VERSION 5.7 ;
  NOWIREEXTENSIONATPIN ON ;
  DIVIDERCHAR "/" ;
  BUSBITCHARS "[]" ;
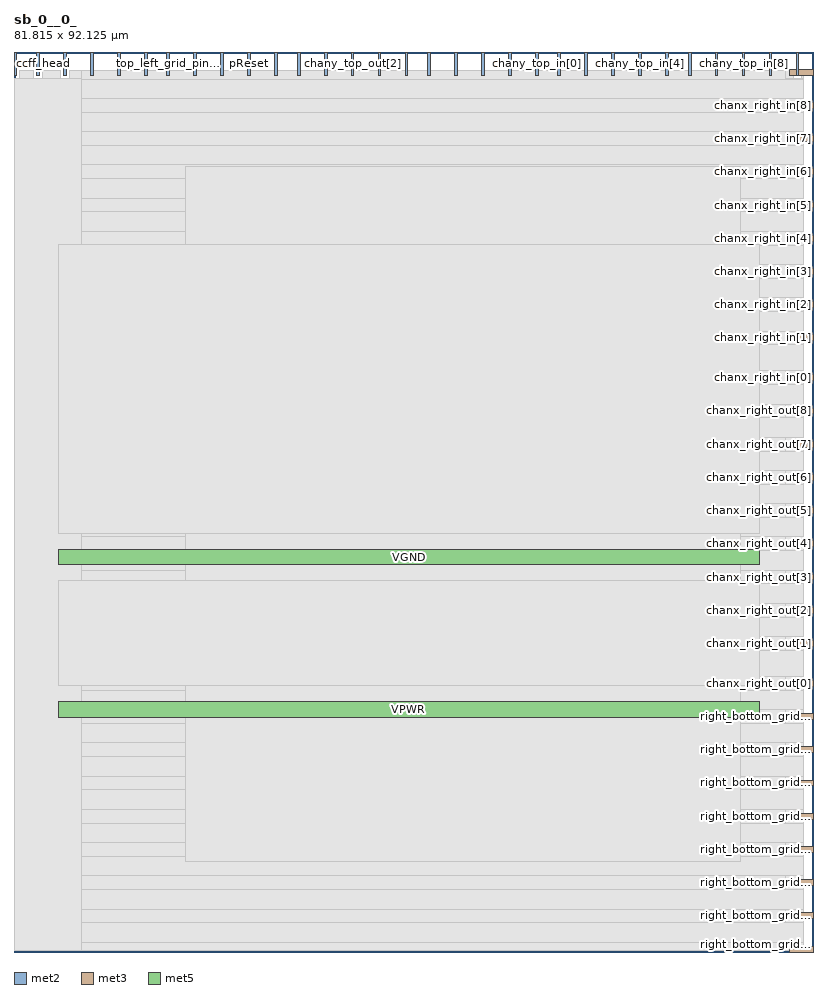
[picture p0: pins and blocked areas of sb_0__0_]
MACRO sb_0__0_
  CLASS BLOCK ;
  FOREIGN sb_0__0_ ;
  ORIGIN 0.000 0.000 ;
  SIZE 81.815 BY 92.125 ;
  PIN ccff_head
    DIRECTION INPUT ;
    PORT
      LAYER met2 ;
        RECT 0.020 89.725 0.300 92.125 ;
    END
  END ccff_head
  PIN ccff_tail
    DIRECTION OUTPUT TRISTATE ;
    PORT
      LAYER met2 ;
        RECT 77.300 89.725 77.580 92.125 ;
    END
  END ccff_tail
  PIN chanx_right_in[0]
    DIRECTION INPUT ;
    PORT
      LAYER met3 ;
        RECT 79.415 58.480 81.815 59.080 ;
    END
  END chanx_right_in[0]
  PIN chanx_right_in[1]
    DIRECTION INPUT ;
    PORT
      LAYER met3 ;
        RECT 79.415 62.560 81.815 63.160 ;
    END
  END chanx_right_in[1]
  PIN chanx_right_in[2]
    DIRECTION INPUT ;
    PORT
      LAYER met3 ;
        RECT 79.415 65.960 81.815 66.560 ;
    END
  END chanx_right_in[2]
  PIN chanx_right_in[3]
    DIRECTION INPUT ;
    PORT
      LAYER met3 ;
        RECT 79.415 69.360 81.815 69.960 ;
    END
  END chanx_right_in[3]
  PIN chanx_right_in[4]
    DIRECTION INPUT ;
    PORT
      LAYER met3 ;
        RECT 79.415 72.760 81.815 73.360 ;
    END
  END chanx_right_in[4]
  PIN chanx_right_in[5]
    DIRECTION INPUT ;
    PORT
      LAYER met3 ;
        RECT 79.415 76.160 81.815 76.760 ;
    END
  END chanx_right_in[5]
  PIN chanx_right_in[6]
    DIRECTION INPUT ;
    PORT
      LAYER met3 ;
        RECT 79.415 79.560 81.815 80.160 ;
    END
  END chanx_right_in[6]
  PIN chanx_right_in[7]
    DIRECTION INPUT ;
    PORT
      LAYER met3 ;
        RECT 79.415 82.960 81.815 83.560 ;
    END
  END chanx_right_in[7]
  PIN chanx_right_in[8]
    DIRECTION INPUT ;
    PORT
      LAYER met3 ;
        RECT 79.415 86.360 81.815 86.960 ;
    END
  END chanx_right_in[8]
  PIN chanx_right_out[0]
    DIRECTION OUTPUT TRISTATE ;
    PORT
      LAYER met3 ;
        RECT 79.415 27.200 81.815 27.800 ;
    END
  END chanx_right_out[0]
  PIN chanx_right_out[1]
    DIRECTION OUTPUT TRISTATE ;
    PORT
      LAYER met3 ;
        RECT 79.415 31.280 81.815 31.880 ;
    END
  END chanx_right_out[1]
  PIN chanx_right_out[2]
    DIRECTION OUTPUT TRISTATE ;
    PORT
      LAYER met3 ;
        RECT 79.415 34.680 81.815 35.280 ;
    END
  END chanx_right_out[2]
  PIN chanx_right_out[3]
    DIRECTION OUTPUT TRISTATE ;
    PORT
      LAYER met3 ;
        RECT 79.415 38.080 81.815 38.680 ;
    END
  END chanx_right_out[3]
  PIN chanx_right_out[4]
    DIRECTION OUTPUT TRISTATE ;
    PORT
      LAYER met3 ;
        RECT 79.415 41.480 81.815 42.080 ;
    END
  END chanx_right_out[4]
  PIN chanx_right_out[5]
    DIRECTION OUTPUT TRISTATE ;
    PORT
      LAYER met3 ;
        RECT 79.415 44.880 81.815 45.480 ;
    END
  END chanx_right_out[5]
  PIN chanx_right_out[6]
    DIRECTION OUTPUT TRISTATE ;
    PORT
      LAYER met3 ;
        RECT 79.415 48.280 81.815 48.880 ;
    END
  END chanx_right_out[6]
  PIN chanx_right_out[7]
    DIRECTION OUTPUT TRISTATE ;
    PORT
      LAYER met3 ;
        RECT 79.415 51.680 81.815 52.280 ;
    END
  END chanx_right_out[7]
  PIN chanx_right_out[8]
    DIRECTION OUTPUT TRISTATE ;
    PORT
      LAYER met3 ;
        RECT 79.415 55.080 81.815 55.680 ;
    END
  END chanx_right_out[8]
  PIN chany_top_in[0]
    DIRECTION INPUT ;
    PORT
      LAYER met2 ;
        RECT 53.380 89.725 53.660 92.125 ;
    END
  END chany_top_in[0]
  PIN chany_top_in[1]
    DIRECTION INPUT ;
    PORT
      LAYER met2 ;
        RECT 55.680 89.725 55.960 92.125 ;
    END
  END chany_top_in[1]
  PIN chany_top_in[2]
    DIRECTION INPUT ;
    PORT
      LAYER met2 ;
        RECT 58.440 89.725 58.720 92.125 ;
    END
  END chany_top_in[2]
  PIN chany_top_in[3]
    DIRECTION INPUT ;
    PORT
      LAYER met2 ;
        RECT 61.200 89.725 61.480 92.125 ;
    END
  END chany_top_in[3]
  PIN chany_top_in[4]
    DIRECTION INPUT ;
    PORT
      LAYER met2 ;
        RECT 63.960 89.725 64.240 92.125 ;
    END
  END chany_top_in[4]
  PIN chany_top_in[5]
    DIRECTION INPUT ;
    PORT
      LAYER met2 ;
        RECT 66.720 89.725 67.000 92.125 ;
    END
  END chany_top_in[5]
  PIN chany_top_in[6]
    DIRECTION INPUT ;
    PORT
      LAYER met2 ;
        RECT 69.020 89.725 69.300 92.125 ;
    END
  END chany_top_in[6]
  PIN chany_top_in[7]
    DIRECTION INPUT ;
    PORT
      LAYER met2 ;
        RECT 71.780 89.725 72.060 92.125 ;
    END
  END chany_top_in[7]
  PIN chany_top_in[8]
    DIRECTION INPUT ;
    PORT
      LAYER met2 ;
        RECT 74.540 89.725 74.820 92.125 ;
    END
  END chany_top_in[8]
  PIN chany_top_out[0]
    DIRECTION OUTPUT TRISTATE ;
    PORT
      LAYER met2 ;
        RECT 29.000 89.725 29.280 92.125 ;
    END
  END chany_top_out[0]
  PIN chany_top_out[1]
    DIRECTION OUTPUT TRISTATE ;
    PORT
      LAYER met2 ;
        RECT 31.760 89.725 32.040 92.125 ;
    END
  END chany_top_out[1]
  PIN chany_top_out[2]
    DIRECTION OUTPUT TRISTATE ;
    PORT
      LAYER met2 ;
        RECT 34.520 89.725 34.800 92.125 ;
    END
  END chany_top_out[2]
  PIN chany_top_out[3]
    DIRECTION OUTPUT TRISTATE ;
    PORT
      LAYER met2 ;
        RECT 37.280 89.725 37.560 92.125 ;
    END
  END chany_top_out[3]
  PIN chany_top_out[4]
    DIRECTION OUTPUT TRISTATE ;
    PORT
      LAYER met2 ;
        RECT 40.040 89.725 40.320 92.125 ;
    END
  END chany_top_out[4]
  PIN chany_top_out[5]
    DIRECTION OUTPUT TRISTATE ;
    PORT
      LAYER met2 ;
        RECT 42.340 89.725 42.620 92.125 ;
    END
  END chany_top_out[5]
  PIN chany_top_out[6]
    DIRECTION OUTPUT TRISTATE ;
    PORT
      LAYER met2 ;
        RECT 45.100 89.725 45.380 92.125 ;
    END
  END chany_top_out[6]
  PIN chany_top_out[7]
    DIRECTION OUTPUT TRISTATE ;
    PORT
      LAYER met2 ;
        RECT 47.860 89.725 48.140 92.125 ;
    END
  END chany_top_out[7]
  PIN chany_top_out[8]
    DIRECTION OUTPUT TRISTATE ;
    PORT
      LAYER met2 ;
        RECT 50.620 89.725 50.900 92.125 ;
    END
  END chany_top_out[8]
  PIN pReset
    DIRECTION INPUT ;
    PORT
      LAYER met2 ;
        RECT 23.940 89.725 24.220 92.125 ;
    END
  END pReset
  PIN prog_clk
    DIRECTION INPUT ;
    PORT
      LAYER met2 ;
        RECT 26.700 89.725 26.980 92.125 ;
    END
  END prog_clk
  PIN right_bottom_grid_pin_11_
    DIRECTION INPUT ;
    PORT
      LAYER met3 ;
        RECT 79.415 17.000 81.815 17.600 ;
    END
  END right_bottom_grid_pin_11_
  PIN right_bottom_grid_pin_13_
    DIRECTION INPUT ;
    PORT
      LAYER met3 ;
        RECT 79.415 20.400 81.815 21.000 ;
    END
  END right_bottom_grid_pin_13_
  PIN right_bottom_grid_pin_15_
    DIRECTION INPUT ;
    PORT
      LAYER met3 ;
        RECT 79.415 23.800 81.815 24.400 ;
    END
  END right_bottom_grid_pin_15_
  PIN right_bottom_grid_pin_1_
    DIRECTION INPUT ;
    PORT
      LAYER met3 ;
        RECT 79.415 0.000 81.815 0.600 ;
    END
  END right_bottom_grid_pin_1_
  PIN right_bottom_grid_pin_3_
    DIRECTION INPUT ;
    PORT
      LAYER met3 ;
        RECT 79.415 3.400 81.815 4.000 ;
    END
  END right_bottom_grid_pin_3_
  PIN right_bottom_grid_pin_5_
    DIRECTION INPUT ;
    PORT
      LAYER met3 ;
        RECT 79.415 6.800 81.815 7.400 ;
    END
  END right_bottom_grid_pin_5_
  PIN right_bottom_grid_pin_7_
    DIRECTION INPUT ;
    PORT
      LAYER met3 ;
        RECT 79.415 10.200 81.815 10.800 ;
    END
  END right_bottom_grid_pin_7_
  PIN right_bottom_grid_pin_9_
    DIRECTION INPUT ;
    PORT
      LAYER met3 ;
        RECT 79.415 13.600 81.815 14.200 ;
    END
  END right_bottom_grid_pin_9_
  PIN right_top_grid_pin_10_
    DIRECTION INPUT ;
    PORT
      LAYER met3 ;
        RECT 79.415 89.760 81.815 90.360 ;
    END
  END right_top_grid_pin_10_
  PIN top_left_grid_pin_11_
    DIRECTION INPUT ;
    PORT
      LAYER met2 ;
        RECT 15.660 89.725 15.940 92.125 ;
    END
  END top_left_grid_pin_11_
  PIN top_left_grid_pin_13_
    DIRECTION INPUT ;
    PORT
      LAYER met2 ;
        RECT 18.420 89.725 18.700 92.125 ;
    END
  END top_left_grid_pin_13_
  PIN top_left_grid_pin_15_
    DIRECTION INPUT ;
    PORT
      LAYER met2 ;
        RECT 21.180 89.725 21.460 92.125 ;
    END
  END top_left_grid_pin_15_
  PIN top_left_grid_pin_1_
    DIRECTION INPUT ;
    PORT
      LAYER met2 ;
        RECT 2.320 89.725 2.600 92.125 ;
    END
  END top_left_grid_pin_1_
  PIN top_left_grid_pin_3_
    DIRECTION INPUT ;
    PORT
      LAYER met2 ;
        RECT 5.080 89.725 5.360 92.125 ;
    END
  END top_left_grid_pin_3_
  PIN top_left_grid_pin_5_
    DIRECTION INPUT ;
    PORT
      LAYER met2 ;
        RECT 7.840 89.725 8.120 92.125 ;
    END
  END top_left_grid_pin_5_
  PIN top_left_grid_pin_7_
    DIRECTION INPUT ;
    PORT
      LAYER met2 ;
        RECT 10.600 89.725 10.880 92.125 ;
    END
  END top_left_grid_pin_7_
  PIN top_left_grid_pin_9_
    DIRECTION INPUT ;
    PORT
      LAYER met2 ;
        RECT 13.360 89.725 13.640 92.125 ;
    END
  END top_left_grid_pin_9_
  PIN top_right_grid_pin_11_
    DIRECTION INPUT ;
    PORT
      LAYER met2 ;
        RECT 80.060 89.725 80.340 92.125 ;
    END
  END top_right_grid_pin_11_
  PIN VPWR
    DIRECTION INPUT ;
    USE POWER ;
    PORT
      LAYER met5 ;
        RECT 4.530 24.030 76.290 25.630 ;
    END
  END VPWR
  PIN VGND
    DIRECTION INPUT ;
    USE GROUND ;
    PORT
      LAYER met5 ;
        RECT 4.530 39.615 76.290 41.215 ;
    END
  END VGND
  OBS
      LAYER li1 ;
        RECT 4.530 9.395 76.290 80.285 ;
      LAYER met1 ;
        RECT 0.000 9.240 76.290 83.220 ;
      LAYER met2 ;
        RECT 0.580 89.445 2.040 90.245 ;
        RECT 2.880 89.445 4.800 90.245 ;
        RECT 5.640 89.445 7.560 90.245 ;
        RECT 8.400 89.445 10.320 90.245 ;
        RECT 11.160 89.445 13.080 90.245 ;
        RECT 13.920 89.445 15.380 90.245 ;
        RECT 16.220 89.445 18.140 90.245 ;
        RECT 18.980 89.445 20.900 90.245 ;
        RECT 21.740 89.445 23.660 90.245 ;
        RECT 24.500 89.445 26.420 90.245 ;
        RECT 27.260 89.445 28.720 90.245 ;
        RECT 29.560 89.445 31.480 90.245 ;
        RECT 32.320 89.445 34.240 90.245 ;
        RECT 35.080 89.445 37.000 90.245 ;
        RECT 37.840 89.445 39.760 90.245 ;
        RECT 40.600 89.445 42.060 90.245 ;
        RECT 42.900 89.445 44.820 90.245 ;
        RECT 45.660 89.445 47.580 90.245 ;
        RECT 48.420 89.445 50.340 90.245 ;
        RECT 51.180 89.445 53.100 90.245 ;
        RECT 53.940 89.445 55.400 90.245 ;
        RECT 56.240 89.445 58.160 90.245 ;
        RECT 59.000 89.445 60.920 90.245 ;
        RECT 61.760 89.445 63.680 90.245 ;
        RECT 64.520 89.445 66.440 90.245 ;
        RECT 67.280 89.445 68.740 90.245 ;
        RECT 69.580 89.445 71.500 90.245 ;
        RECT 72.340 89.445 74.260 90.245 ;
        RECT 75.100 89.445 77.020 90.245 ;
        RECT 77.860 89.445 79.780 90.245 ;
        RECT 80.620 89.445 80.800 90.245 ;
        RECT 0.030 0.115 80.800 89.445 ;
      LAYER met3 ;
        RECT 6.895 89.360 79.015 90.225 ;
        RECT 6.895 87.360 80.825 89.360 ;
        RECT 6.895 85.960 79.015 87.360 ;
        RECT 6.895 83.960 80.825 85.960 ;
        RECT 6.895 82.560 79.015 83.960 ;
        RECT 6.895 80.560 80.825 82.560 ;
        RECT 6.895 79.160 79.015 80.560 ;
        RECT 6.895 77.160 80.825 79.160 ;
        RECT 6.895 75.760 79.015 77.160 ;
        RECT 6.895 73.760 80.825 75.760 ;
        RECT 6.895 72.360 79.015 73.760 ;
        RECT 6.895 70.360 80.825 72.360 ;
        RECT 6.895 68.960 79.015 70.360 ;
        RECT 6.895 66.960 80.825 68.960 ;
        RECT 6.895 65.560 79.015 66.960 ;
        RECT 6.895 63.560 80.825 65.560 ;
        RECT 6.895 62.160 79.015 63.560 ;
        RECT 6.895 59.480 80.825 62.160 ;
        RECT 6.895 58.080 79.015 59.480 ;
        RECT 6.895 56.080 80.825 58.080 ;
        RECT 6.895 54.680 79.015 56.080 ;
        RECT 6.895 52.680 80.825 54.680 ;
        RECT 6.895 51.280 79.015 52.680 ;
        RECT 6.895 49.280 80.825 51.280 ;
        RECT 6.895 47.880 79.015 49.280 ;
        RECT 6.895 45.880 80.825 47.880 ;
        RECT 6.895 44.480 79.015 45.880 ;
        RECT 6.895 42.480 80.825 44.480 ;
        RECT 6.895 41.080 79.015 42.480 ;
        RECT 6.895 39.080 80.825 41.080 ;
        RECT 6.895 37.680 79.015 39.080 ;
        RECT 6.895 35.680 80.825 37.680 ;
        RECT 6.895 34.280 79.015 35.680 ;
        RECT 6.895 32.280 80.825 34.280 ;
        RECT 6.895 30.880 79.015 32.280 ;
        RECT 6.895 28.200 80.825 30.880 ;
        RECT 6.895 26.800 79.015 28.200 ;
        RECT 6.895 24.800 80.825 26.800 ;
        RECT 6.895 23.400 79.015 24.800 ;
        RECT 6.895 21.400 80.825 23.400 ;
        RECT 6.895 20.000 79.015 21.400 ;
        RECT 6.895 18.000 80.825 20.000 ;
        RECT 6.895 16.600 79.015 18.000 ;
        RECT 6.895 14.600 80.825 16.600 ;
        RECT 6.895 13.200 79.015 14.600 ;
        RECT 6.895 11.200 80.825 13.200 ;
        RECT 6.895 9.800 79.015 11.200 ;
        RECT 6.895 7.800 80.825 9.800 ;
        RECT 6.895 6.400 79.015 7.800 ;
        RECT 6.895 4.400 80.825 6.400 ;
        RECT 6.895 3.000 79.015 4.400 ;
        RECT 6.895 1.000 80.825 3.000 ;
        RECT 6.895 0.135 79.015 1.000 ;
      LAYER met4 ;
        RECT 17.530 9.240 74.335 80.440 ;
      LAYER met5 ;
        RECT 4.530 42.815 76.290 72.390 ;
        RECT 4.530 27.230 76.290 38.015 ;
  END
END sb_0__0_
END LIBRARY

